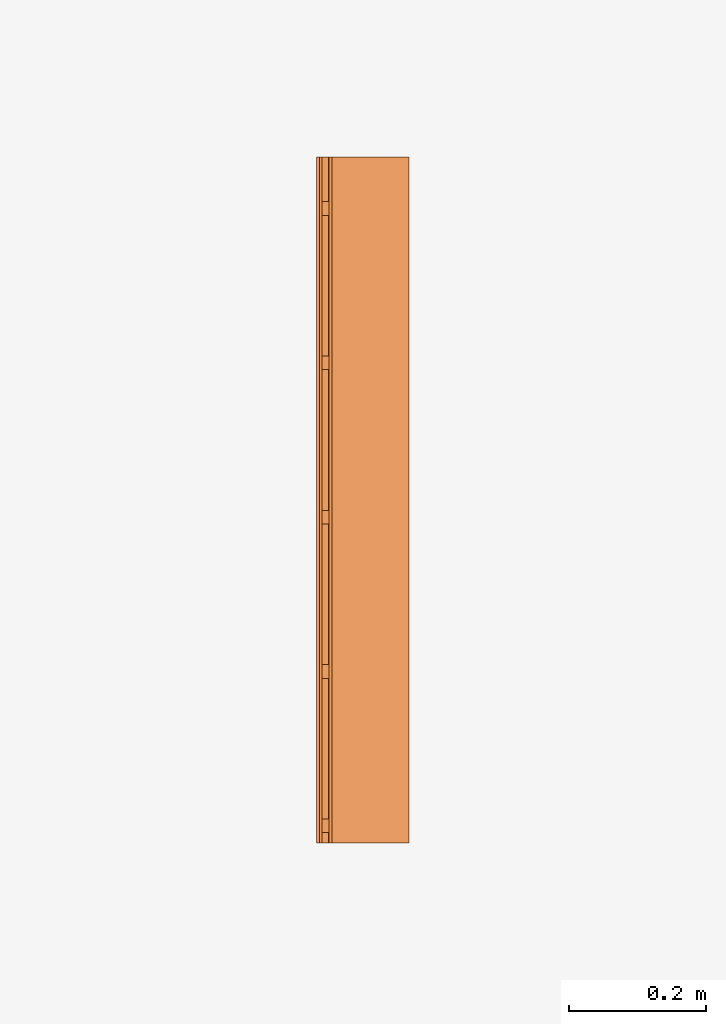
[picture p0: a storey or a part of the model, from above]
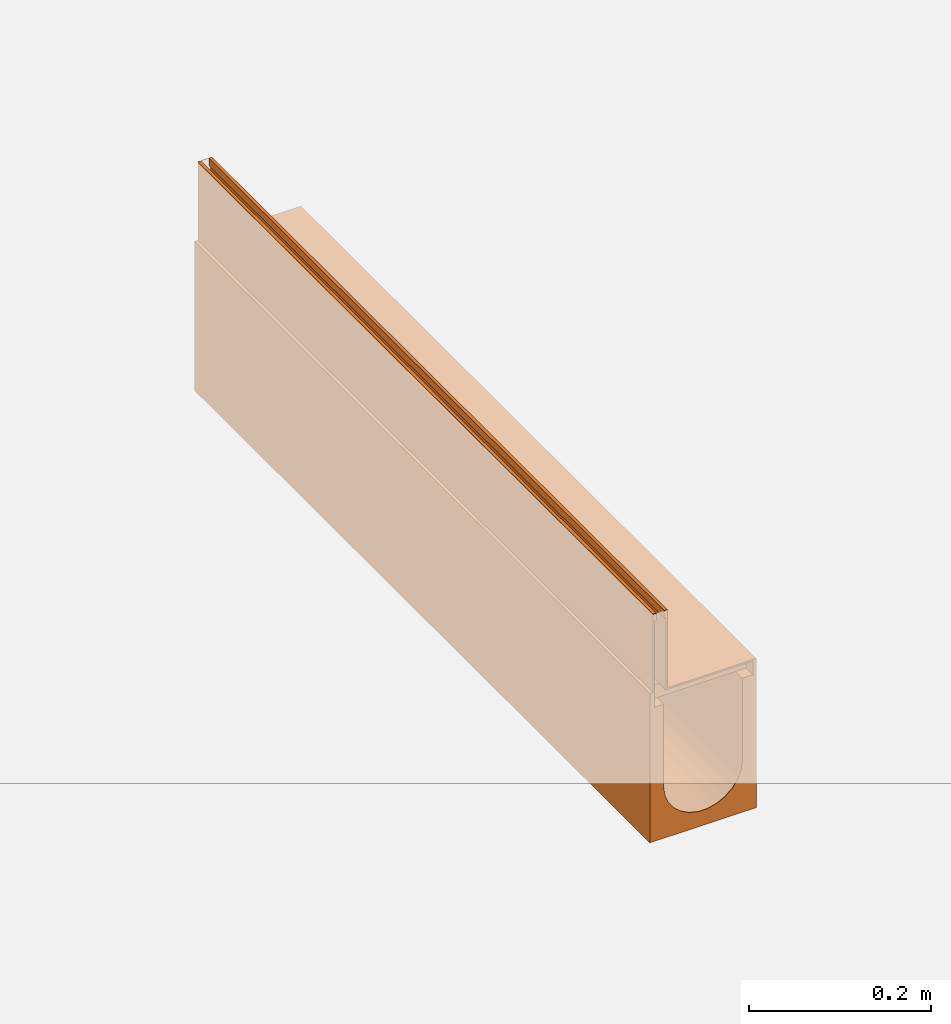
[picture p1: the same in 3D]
Properties of the parts of a building model (IFC2X3)

# File
Description: ViewDefinition [CoordinationView]
File name: 24100.ifc
Time: 2013-10-30T12:01:40
Written by: Autodesk Revit 2013
Made in: 20120221_2030(x64)

# IfcProject, Project Number
LongName: Project Name; Phase: Project Status

# IfcSite, Default
RefLatitude: 42, 21, 30, 344238; RefLongitude: -71, -3, -35, -194702; RefElevation: 0 mm

# IfcBuilding
Pset_BuildingCommon - NumberOfStoreys: 1
Other - Project Issue Date: Issue Date; Project Name: Project Name; Project Status: Project Status; Client Name: Owner; Project Address: ## Street City, State Zip; Project Number: Project Number

# IfcBuildingStorey, Level 1
LongName: Level 1; Elevation: 0 mm
Constraints - Elevation Base: 0; Elevation: 0 mm
Graphics - Symbol at End 1 Default: no; Line Pattern: Center; Symbol: M_Level Head - Circle: M_Level Head - Circle; Line Weight: 1; Color: 0; Symbol at End 2 Default: yes
Identity Data - Structural: no; Building Story: yes; Name: Level 1
Dimensions - Computation Height: 0 mm

# IfcBuildingElementProxy: 24100 - No 10.0 Constant Depth Channel - 1000mm LG - Invert Depth 180mm, Civil-Drainage-Channel-ACO-MultiDrain-M100DS-Brickslot-Channel-System:24100 - No 10.0 Constant Depth Channel - 1000mm LG - Invert Depth 180mm:24100 - No 10.0 Constant Depth Channel - 1000mm LG - Invert Depth 180mm:196059
In: Level 1
Material: Vienite® Synthetic Resin Concrete, Stainless Steel (F)
Constraints - Moves With Nearby Elements: no; Level: Level: Level 1
Dimensions - Length: 1000 mm; EndCap Position: 1000 mm; Custom_Void_length: 0 mm; FloorCut_Length: -1000 mm; Brickslot Void Length: 1000 mm; Volume: 10337851 mm3; Brickslot Access Unit Void Bottom Depth: -6605 mm; Brickslot Access Unit Void Depth: -6500 mm; Brickslot Void Depth: 0 mm; FloorCut_Width: 135 mm; ShallowInvDepth: 55 mm; Floor Cut Gap: 105 mm; Brickslot Access Unit Floor Cut Length: 500 mm; ShallowOverallDepth: 75 mm; InvDepth: 130 mm; FloorCut_Depth: 200 mm; GratingLength: -1000 mm; EndCap_Height: 200 mm; Depth: 200 mm; Length Drain: -1000 mm
Construction - 23404_Universal Endcap (Male End): no; 23476_Load Class C250 & D400_Brickslot Grating_Stainless Steel_500mm Long: no; 23477_Load Class C250 & D400_Brickslot_Access Unit_Stainless Steel_500mm Long: no; 23404_Universal Endcap (Female End): no; 23475_Load Class C250 & D400_Brickslot Grating_Stainless Steel_1000mm Long: yes; Shallow Depth Channel with seal: no; 23410_Sump Unit: no; Constant Depth Junction Channel: no; Shallow Depth Channel: no; Constant Depth Channel: yes
Phasing - Phase Created: New Construction
Pset_BuildingElementProxyCommon - Reference: 24100 - No 10.0 Constant Depth Channel - 1000mm LG - Invert Depth 180mm
Data - Product Dimensions: 1000mm x 135mm x 200mm (LxWxH); ACO Hydraulic Design Software: http://www.acodesign.co.uk; Installation - Concrete Grade: Refer to brochure; Hydraulic Performance: http://www.aco.co.uk/download.php?id=173; Concrete Surround Volume - Load Class D 400 - Concrete Pavement: 0.19m³/m; Concrete Surround Volume - Load Class A 15 - Concrete Pavement: 0.08m³/m; Product Weight: 17.9 Kg; Concrete Surround Volume - Load Class B 125 - C 250 - Concrete Pavement: 0.13m³/m; Channel C.S.A: 0.013m²; Load Class: A 15 - D 400; Product Standard: BS EN 1433:2002, CE marked; Pre-formed Outlet Ø: N/A; Invert Depth: 180mm
General - TagNumber: 0; SerialNumber: 0
Identity Data - Installation guidelines: http://www.aco.co.uk/download.php?id=173; Type Comments: ACO MultiDrain M100DS 10.0 Constant Depth Channel 1000mm Long; Watermark 1: This file is the property of ACO Technologies PLC; Cost: 0; Manufacturer: ACO Technologies plc - ACO Water Management Division; Address: ACO Business Park, Hitchin Road, Shefford, Bedfordshire, United Kingdom SG17 5TE; Product brochure: http://www.aco.co.uk/download.php?id=173; Product Code: 24100; Product Page URL: http://www.aco.co.uk/product_detail.php?id=58; Telephone: +44 (0)1462 816666; URL: www.aco.co.uk; Fax: +44 (0)1462 815895; Watermarked By: www.aco.co.uk; e-mail Technical: technical@aco.co.uk; Watermark 2: This file is water marked and users are prohibited to reproduce, adapt, distribute this information; Model: ACO MultiDrain MDS Brickslot- M100DS; Assembly Code: D2040; Model Description: Channel drainage system; Maintenance guidelines: http://www.aco.co.uk/download.php?id=173; Watermarked With: BIM Manager Premium Suite; OmniClass Title: Rainwater Removal; Assembly Description: Rain Water Drainage; e-mail Sales: customersupport@aco.co.uk; OmniClass Number: 23.70.50.24; Price: POA - contact ACO
Model Properties - Brickslot Grating Product code 23475: Load Class C250/D400 - Brickslot Stainless Steel - 1000mm long x 105mm high -10mm Slot- Intake area - 1000mm²/m - 6.6 Kg; Brickslot Grating Product code 23476: Load Class C250/D400 - Brickslot Stainless Steel - 500mm long x 105mm high -10mm Slot- Intake area - 1000mm²/m - 3.3 Kg; Brickslot Access Unit Product code 23477: Load Class C250/D400 - Brickslot Access Unit Stainless Steel - 500mm long x 105mm high -10mm Slot- Intake area - 1000mm²/m - 6.4 Kg; End Cap Product code 23404: No 306 Universl End Cap - 135mm wide x 300mm long - Spigot Ø110mm x 50mm long - Silver - Polypropylene - 0.16kg
Green Building Properties - Channel Recyclable: Fully recyclable; Edge Rail Recyclable: Fully recyclable; Edge Rail Recycled Material Content: Between 40% - 90%; Channel Recycled Material Content: 20% minimum
Materials and Finishes - Channel Colour: Brown; Edge Rail Material: Stainless Steel Grade 304; Edge Rail Colour: Self; Channel Material: Vienite® Synthetic Resin Concrete
Other - Created By: www.aco.co.uk; Revision: 1

# IfcOpeningElement: Recess (2)
In: Level 1
Constraints - Related to Mass: no; Room Bounding: yes; Height Offset From Level: 0 mm; Level: Level: Level 1
Dimensions - Thickness: 400 mm; Volume: 9971110000 mm3; Area: 25000000 mm2; Perimeter: 20000 mm
Structural - Enable Analytical Model: no; Structural: no
Phasing - Phase Created: New Construction
Construction - Function: 0; Default Thickness: 400 mm
Materials and Finishes - Structural Material: Earth
Analytical Properties - Thermal mass: 543920; Roughness: 1; Thermal Resistance (R): 0.477897; Heat Transfer Coefficient (U): 2.0925; Absorptance: 0.1
Graphics - Coarse Scale Fill Color: 0

# IfcSlab: Floor:Generic Floor - 400mm, Floor:Generic Floor - 400mm:193825
In: Level 1
PredefinedType: FLOOR; Material: Earth 400 mm
Constraints - Related to Mass: no; Room Bounding: yes; Height Offset From Level: 0 mm; Level: Level: Level 1
Dimensions - Thickness: 400 mm; Volume: 9971110000 mm3; Area: 25000000 mm2; Perimeter: 20000 mm
Structural - Enable Analytical Model: no; Structural: no
Phasing - Phase Created: New Construction
Pset_SlabCommon - Reference: Generic Floor - 400mm; IsExternal: no; LoadBearing: yes
Construction - Function: 0; Default Thickness: 400 mm
Materials and Finishes - Structural Material: Earth
Analytical Properties - Thermal mass: 543920; Roughness: 1; Thermal Resistance (R): 0.477897; Heat Transfer Coefficient (U): 2.0925; Absorptance: 0.1
Graphics - Coarse Scale Fill Color: 0
